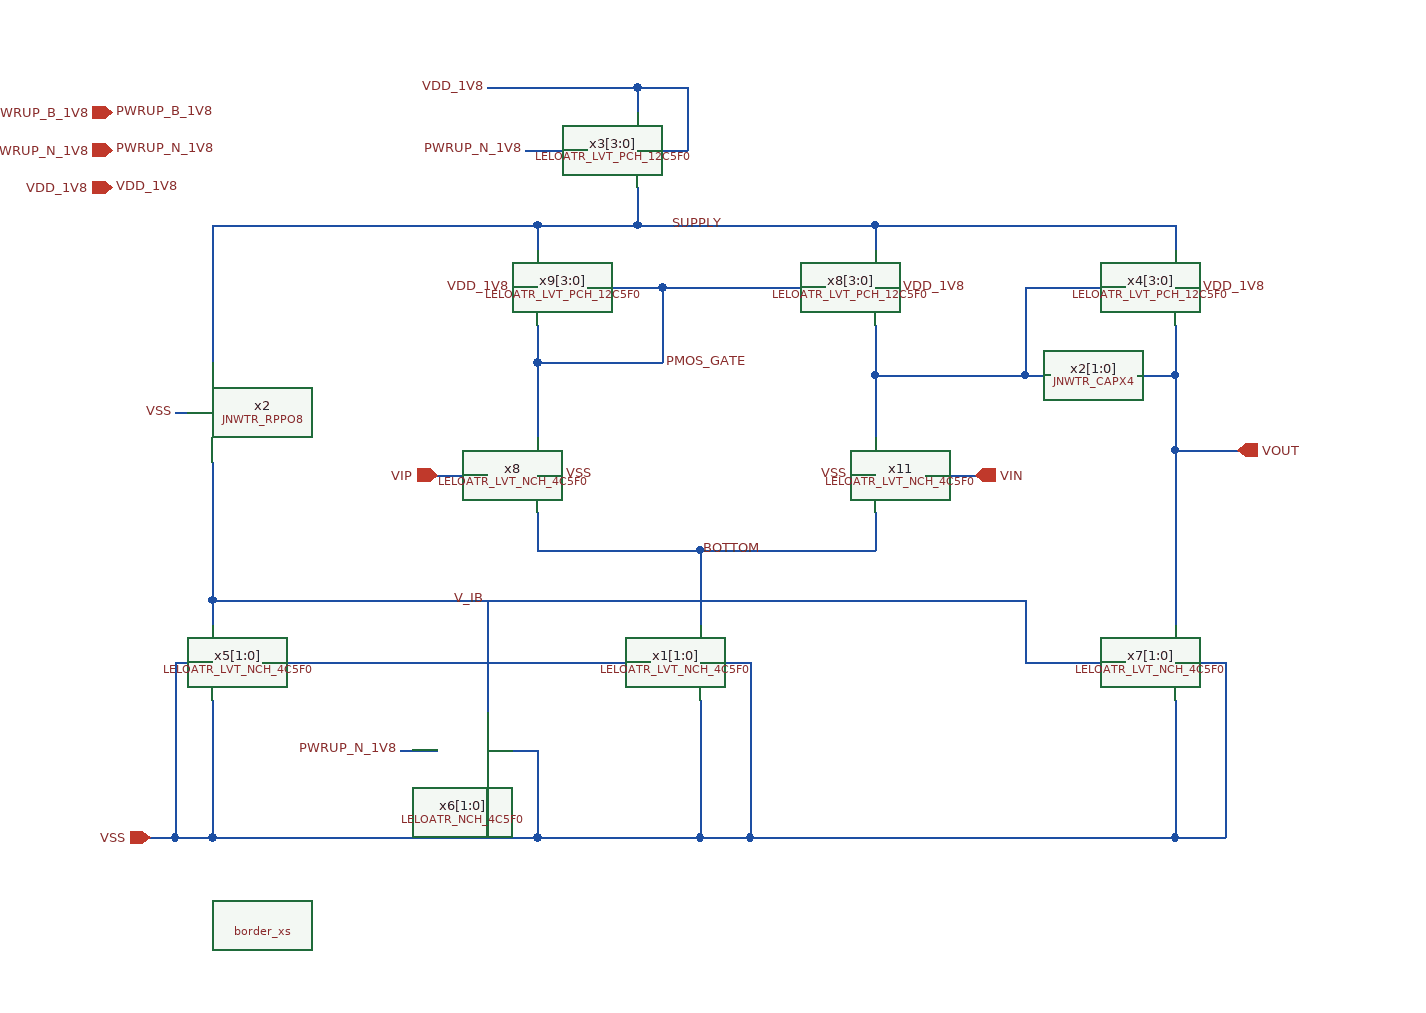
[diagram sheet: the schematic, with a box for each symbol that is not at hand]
v {xschem version=3.4.7 file_version=1.2}
G {}
K {}
V {}
S {}
E {}
N -590 -470 -530 -470 {lab=PMOS_GATE}
N -630 -410 -630 -350 {lab=PMOS_GATE}
N -360 -400 -360 -350 {lab=#net1}
N -630 -410 -530 -410 {lab=PMOS_GATE}
N -320 -320 -280 -320 {lab=VIN}
N -630 -290 -630 -260 {lab=BOTTOM}
N -360 -290 -360 -260 {lab=BOTTOM}
N -530 -470 -530 -410 {lab=PMOS_GATE}
N -500 -260 -360 -260 {lab=BOTTOM}
N -500 -240 -500 -200 {lab=BOTTOM}
N -700 -170 -540 -170 {lab=V_IB}
N -920 -170 -890 -170 {lab=VSS}
N -500 -170 -470 -170 {lab=VSS}
N -360 -520 -360 -500 {lab=SUPPLY}
N -550 -520 -360 -520 {lab=SUPPLY}
N -630 -520 -630 -500 {lab=SUPPLY}
N -360 -470 -340 -470 {lab=VDD_1V8}
N -640 -580 -590 -580 {lab=PWRUP_N_1V8}
N -670 -630 -550 -630 {lab=VDD_1V8}
N -550 -630 -550 -610 {lab=VDD_1V8}
N -550 -550 -550 -520 {lab=SUPPLY}
N -550 -580 -510 -580 {lab=VDD_1V8}
N -510 -630 -510 -580 {lab=VDD_1V8}
N -550 -630 -510 -630 {lab=VDD_1V8}
N -650 -470 -630 -470 {lab=VDD_1V8}
N -630 -320 -610 -320 {lab=VSS}
N -380 -320 -360 -320 {lab=VSS}
N -360 -520 -120 -520 {lab=SUPPLY}
N -120 -520 -120 -500 {lab=SUPPLY}
N -120 -470 -100 -470 {lab=VDD_1V8}
N -120 -170 -90 -170 {lab=VSS}
N -120 -340 -70 -340 {lab=VOUT}
N -710 -320 -670 -320 {lab=VIP}
N -890 -220 -890 -200 {lab=V_IB}
N -920 -370 -910 -370 {lab=VSS}
N -120 -440 -120 -400 {lab=VOUT}
N -120 -320 -120 -200 {lab=VOUT}
N -240 -400 -220 -400 {lab=#net1}
N -150 -400 -120 -400 {lab=VOUT}
N -240 -470 -240 -400 {lab=#net1}
N -240 -470 -160 -470 {lab=#net1}
N -360 -400 -240 -400 {lab=#net1}
N -630 -260 -500 -260 {lab=BOTTOM}
N -850 -170 -700 -170 {lab=V_IB}
N -920 -30 -890 -30 {lab=VSS}
N -630 -440 -630 -410 {lab=PMOS_GATE}
N -630 -520 -550 -520 {lab=SUPPLY}
N -120 -400 -120 -340 {lab=VOUT}
N -360 -440 -360 -400 {lab=#net1}
N -890 -140 -890 -120 {lab=VSS}
N -850 -30 -700 -30 {lab=VSS}
N -920 -170 -920 -60 {lab=VSS}
N -120 -140 -120 -110 {lab=VSS}
N -890 -90 -890 -60 {lab=VSS}
N -240 -170 -160 -170 {lab=V_IB}
N -240 -220 -240 -170 {lab=V_IB}
N -890 -120 -890 -90 {lab=VSS}
N -920 -60 -920 -30 {lab=VSS}
N -890 -430 -890 -410 {lab=SUPPLY}
N -890 -250 -890 -220 {lab=V_IB}
N -890 -220 -810 -220 {lab=V_IB}
N -670 -170 -670 -130 {lab=V_IB}
N -740 -100 -710 -100 {lab=PWRUP_N_1V8}
N -670 -100 -630 -100 {lab=VSS}
N -630 -100 -630 -30 {lab=VSS}
N -700 -30 -630 -30 {lab=VSS}
N -890 -60 -890 -30 {lab=VSS}
N -890 -30 -850 -30 {lab=VSS}
N -940 -30 -920 -30 {lab=VSS}
N -670 -70 -670 -30 {lab=VSS}
N -500 -140 -500 -30 {lab=VSS}
N -630 -30 -500 -30 {lab=VSS}
N -470 -170 -460 -170 {lab=VSS}
N -460 -170 -460 -30 {lab=VSS}
N -500 -30 -460 -30 {lab=VSS}
N -120 -110 -120 -30 {lab=VSS}
N -460 -30 -120 -30 {lab=VSS}
N -810 -220 -240 -220 {lab=V_IB}
N -120 -30 -80 -30 {lab=VSS}
N -80 -170 -80 -30 {lab=VSS}
N -90 -170 -80 -170 {lab=VSS}
N -530 -470 -400 -470 {lab=PMOS_GATE}
N -740 -520 -630 -520 {lab=SUPPLY}
N -890 -310 -890 -250 {lab=V_IB}
N -890 -520 -890 -430 {lab=SUPPLY}
N -890 -520 -740 -520 {lab=SUPPLY}
N -500 -260 -500 -240 {lab=BOTTOM}
N -890 -330 -890 -310 {lab=V_IB}
N -670 -220 -670 -170 {lab=V_IB}
N -120 -340 -120 -320 {lab=VOUT}
C {cborder/border_xs.sym} -850 40 0 0 {
user="Group 2"
company=""}
C {devices/ipin.sym} -940 -30 0 0 {name=p2 lab=VSS}
C {devices/ipin.sym} -970 -580 0 0 {name=p3 lab=PWRUP_N_1V8}
C {devices/ipin.sym} -710 -320 0 0 {name=p4 lab=VIP}
C {devices/opin.sym} -70 -340 0 0 {name=p6 lab=VOUT}
C {devices/lab_wire.sym} -480 -520 0 0 {name=p7 sig_type=std_logic lab=SUPPLY}
C {devices/lab_wire.sym} -530 -410 2 0 {name=p8 sig_type=std_logic lab=PMOS_GATE}
C {devices/lab_pin.sym} -650 -470 0 0 {name=p9 sig_type=std_logic lab=VDD_1V8}
C {devices/lab_pin.sym} -340 -470 0 1 {name=p12 sig_type=std_logic lab=VDD_1V8}
C {devices/lab_wire.sym} -610 -320 0 1 {name=p13 sig_type=std_logic lab=VSS}
C {devices/lab_wire.sym} -380 -320 0 0 {name=p14 sig_type=std_logic lab=VSS}
C {devices/lab_pin.sym} -100 -470 0 1 {name=p15 sig_type=std_logic lab=VDD_1V8}
C {devices/lab_wire.sym} -670 -220 0 0 {name=p19 sig_type=std_logic lab=V_IB}
C {devices/ipin.sym} -280 -320 0 1 {name=p11 lab=VIN}
C {devices/lab_wire.sym} -920 -370 0 0 {name=p5 sig_type=std_logic lab=VSS}
C {JNW_TR_SKY130A/JNWTR_CAPX4.sym} -160 -400 3 1 {name=x2[1:0]}
C {devices/ipin.sym} -970 -610 0 0 {name=p20 lab=PWRUP_B_1V8}
C {devices/lab_pin.sym} -970 -610 0 1 {name=p21 sig_type=std_logic lab=PWRUP_B_1V8}
C {LELO_ATR_SKY130A/LELOATR_LVT_NCH_4C5F0.sym} -540 -170 0 0 {name=x1[1:0]}
C {devices/lab_pin.sym} -970 -580 0 1 {name=p22 sig_type=std_logic lab=PWRUP_N_1V8}
C {devices/lab_pin.sym} -640 -580 0 0 {name=p23 sig_type=std_logic lab=PWRUP_N_1V8}
C {devices/lab_pin.sym} -740 -100 0 0 {name=p24 sig_type=std_logic lab=PWRUP_N_1V8}
C {devices/ipin.sym} -970 -550 0 0 {name=p25 lab=VDD_1V8}
C {devices/lab_pin.sym} -970 -550 0 1 {name=p26 sig_type=std_logic lab=VDD_1V8}
C {devices/lab_pin.sym} -670 -630 0 0 {name=p1 sig_type=std_logic lab=VDD_1V8}
C {devices/lab_wire.sym} -500 -260 0 1 {name=p18 sig_type=std_logic lab=BOTTOM}
C {JNW_TR_SKY130A/JNWTR_RPPO8.sym} -890 -410 1 0 {name=x2 }
C {LELO_ATR_SKY130A/LELOATR_LVT_PCH_12C5F0.sym} -590 -580 0 0 {name=x3[3:0]}
C {LELO_ATR_SKY130A/LELOATR_NCH_4C5F0.sym} -710 -100 0 0 {name=x6[1:0]}
C {LELO_ATR_SKY130A/LELOATR_LVT_NCH_4C5F0.sym} -850 -170 0 1 {name=x5[1:0]}
C {LELO_ATR_SKY130A/LELOATR_LVT_NCH_4C5F0.sym} -160 -170 0 0 {name=x7[1:0]}
C {LELO_ATR_SKY130A/LELOATR_LVT_NCH_4C5F0.sym} -670 -320 0 0 {name=x8}
C {LELO_ATR_SKY130A/LELOATR_LVT_NCH_4C5F0.sym} -320 -320 0 1 {name=x11}
C {LELO_ATR_SKY130A/LELOATR_LVT_PCH_12C5F0.sym} -400 -470 0 0 {name=x8[3:0]}
C {LELO_ATR_SKY130A/LELOATR_LVT_PCH_12C5F0.sym} -160 -470 0 0 {name=x4[3:0]}
C {LELO_ATR_SKY130A/LELOATR_LVT_PCH_12C5F0.sym} -590 -470 0 1 {name=x9[3:0]}
